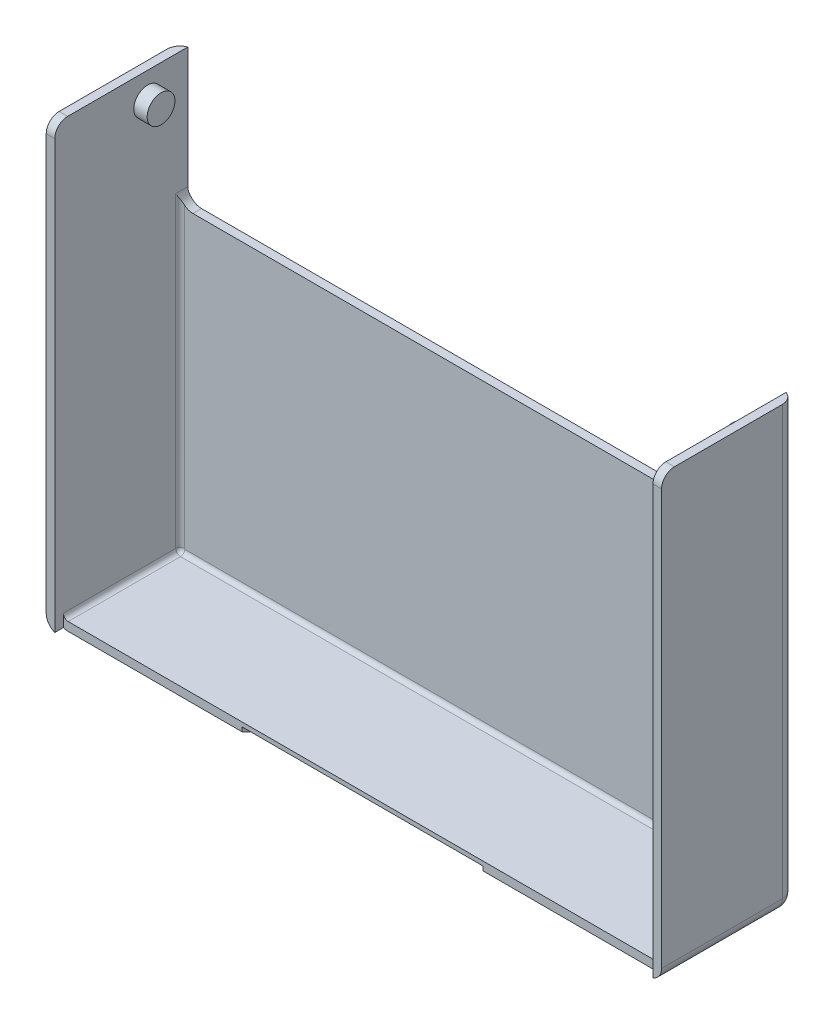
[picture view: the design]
ISO-10303-21;
HEADER;
FILE_DESCRIPTION(('STEP AP214'),'2;1');
FILE_NAME('part.step','',(''),(''),'','','');
FILE_SCHEMA(('AUTOMOTIVE_DESIGN { 1 0 10303 214 1 1 1 1 }'));
ENDSEC;
DATA;
#1=APPLICATION_CONTEXT('core data for automotive mechanical design processes');
#2=APPLICATION_PROTOCOL_DEFINITION('international standard','automotive_design',2000,#1);
#3=PRODUCT_CONTEXT('',#1,'mechanical');
#4=PRODUCT('Part','Part','',(#3));
#5=PRODUCT_RELATED_PRODUCT_CATEGORY('part','',(#4));
#6=PRODUCT_DEFINITION_FORMATION('','',#4);
#7=PRODUCT_DEFINITION_CONTEXT('part definition',#1,'design');
#8=PRODUCT_DEFINITION('design','',#6,#7);
#9=PRODUCT_DEFINITION_SHAPE('','',#8);
#10=(LENGTH_UNIT() NAMED_UNIT(*) SI_UNIT(.MILLI.,.METRE.));
#11=(NAMED_UNIT(*) PLANE_ANGLE_UNIT() SI_UNIT($,.RADIAN.));
#12=(NAMED_UNIT(*) SI_UNIT($,.STERADIAN.) SOLID_ANGLE_UNIT());
#13=UNCERTAINTY_MEASURE_WITH_UNIT(LENGTH_MEASURE(1.E-05),#10,'distance_accuracy_value','');
#14=(GEOMETRIC_REPRESENTATION_CONTEXT(3) GLOBAL_UNCERTAINTY_ASSIGNED_CONTEXT((#13)) GLOBAL_UNIT_ASSIGNED_CONTEXT((#10,
#11,#12)) REPRESENTATION_CONTEXT('',''));
#15=CARTESIAN_POINT('',(0.,0.,0.));
#16=DIRECTION('',(0.,0.,1.));
#17=DIRECTION('',(1.,0.,0.));
#18=AXIS2_PLACEMENT_3D('',#15,#16,#17);
#19=CARTESIAN_POINT('',(-36.5125,52.3875,7.9375));
#20=DIRECTION('',(0.,0.,-1.));
#21=DIRECTION('',(-1.,0.,0.));
#22=AXIS2_PLACEMENT_3D('',#19,#20,#21);
#23=PLANE('',#22);
#24=CARTESIAN_POINT('',(-34.925,1.5875,7.9375));
#25=DIRECTION('',(0.,0.,-1.));
#26=DIRECTION('',(-1.,0.,0.));
#27=AXIS2_PLACEMENT_3D('',#24,#25,#26);
#28=CIRCLE('',#27,1.5875);
#29=CARTESIAN_POINT('',(-36.5125,1.5875,7.9375));
#30=VERTEX_POINT('',#29);
#31=CARTESIAN_POINT('',(-35.4965,0.106438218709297,7.9375));
#32=VERTEX_POINT('',#31);
#33=EDGE_CURVE('E398',#30,#32,#28,.F.);
#34=ORIENTED_EDGE('',*,*,#33,.T.);
#35=DIRECTION('',(0.,-1.,0.));
#36=VECTOR('',#35,1.);
#37=CARTESIAN_POINT('',(-35.4965,52.3875,7.9375));
#38=LINE('',#37,#36);
#39=CARTESIAN_POINT('',(-35.4965,50.8635,7.9375));
#40=VERTEX_POINT('',#39);
#41=EDGE_CURVE('E365',#40,#32,#38,.T.);
#42=ORIENTED_EDGE('',*,*,#41,.F.);
#43=DIRECTION('',(-1.,0.,0.));
#44=VECTOR('',#43,1.);
#45=CARTESIAN_POINT('',(-36.5125,50.8635,7.9375));
#46=LINE('',#45,#44);
#47=CARTESIAN_POINT('',(-36.5125,50.8635,7.9375));
#48=VERTEX_POINT('',#47);
#49=EDGE_CURVE('E435',#40,#48,#46,.T.);
#50=ORIENTED_EDGE('',*,*,#49,.T.);
#51=DIRECTION('',(0.,-1.,0.));
#52=VECTOR('',#51,1.);
#53=CARTESIAN_POINT('',(-36.5125,0.,7.9375));
#54=LINE('',#53,#52);
#55=EDGE_CURVE('E381',#48,#30,#54,.T.);
#56=ORIENTED_EDGE('',*,*,#55,.T.);
#57=EDGE_LOOP('',(#34,#42,#50,#56));
#58=FACE_BOUND('',#57,.T.);
#59=ADVANCED_FACE('F33',(#58),#23,.F.);
#60=CARTESIAN_POINT('',(-35.4965,0.,7.9375));
#61=DIRECTION('',(1.,0.,0.));
#62=DIRECTION('',(0.,0.,-1.));
#63=AXIS2_PLACEMENT_3D('',#60,#61,#62);
#64=PLANE('',#63);
#65=CARTESIAN_POINT('',(-35.4965,50.8635,6.4135));
#66=DIRECTION('',(1.,0.,0.));
#67=DIRECTION('',(0.,0.,-1.));
#68=AXIS2_PLACEMENT_3D('',#65,#66,#67);
#69=CIRCLE('',#68,1.524);
#70=CARTESIAN_POINT('',(-35.4965,52.3875,6.4135));
#71=VERTEX_POINT('',#70);
#72=EDGE_CURVE('E456',#71,#40,#69,.T.);
#73=ORIENTED_EDGE('',*,*,#72,.T.);
#74=ORIENTED_EDGE('',*,*,#41,.T.);
#75=DIRECTION('',(0.,0.,-1.));
#76=VECTOR('',#75,1.);
#77=CARTESIAN_POINT('',(-35.4965,0.106438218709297,7.9375));
#78=LINE('',#77,#76);
#79=CARTESIAN_POINT('',(-35.4965,0.106438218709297,6.9215));
#80=VERTEX_POINT('',#79);
#81=EDGE_CURVE('E278',#32,#80,#78,.T.);
#82=ORIENTED_EDGE('',*,*,#81,.T.);
#83=DIRECTION('',(0.,-1.,0.));
#84=VECTOR('',#83,1.);
#85=CARTESIAN_POINT('',(-35.4965,52.3875,6.9215));
#86=LINE('',#85,#84);
#87=CARTESIAN_POINT('',(-35.4965,1.5875,6.9215));
#88=VERTEX_POINT('',#87);
#89=EDGE_CURVE('E56',#88,#80,#86,.T.);
#90=ORIENTED_EDGE('',*,*,#89,.F.);
#91=DIRECTION('',(0.,0.,-1.));
#92=VECTOR('',#91,1.);
#93=CARTESIAN_POINT('',(-35.4965,1.5875,7.9375));
#94=LINE('',#93,#92);
#95=CARTESIAN_POINT('',(-35.4965,1.5875,-6.4135));
#96=VERTEX_POINT('',#95);
#97=EDGE_CURVE('E325',#96,#88,#94,.F.);
#98=ORIENTED_EDGE('',*,*,#97,.F.);
#99=DIRECTION('',(0.,1.,0.));
#100=VECTOR('',#99,1.);
#101=CARTESIAN_POINT('',(-35.4965,0.,-6.4135));
#102=LINE('',#101,#100);
#103=CARTESIAN_POINT('',(-35.4965,38.0365,-6.4135));
#104=VERTEX_POINT('',#103);
#105=EDGE_CURVE('E322',#104,#96,#102,.F.);
#106=ORIENTED_EDGE('',*,*,#105,.F.);
#107=DIRECTION('',(0.,0.,1.));
#108=VECTOR('',#107,1.);
#109=CARTESIAN_POINT('',(-35.4965,38.0365,7.9375));
#110=LINE('',#109,#108);
#111=CARTESIAN_POINT('',(-35.4965,38.0365,-7.85034097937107));
#112=VERTEX_POINT('',#111);
#113=EDGE_CURVE('E454',#104,#112,#110,.F.);
#114=ORIENTED_EDGE('',*,*,#113,.T.);
#115=DIRECTION('',(0.,1.,0.));
#116=VECTOR('',#115,1.);
#117=CARTESIAN_POINT('',(-35.4965,0.,-7.85034097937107));
#118=LINE('',#117,#116);
#119=CARTESIAN_POINT('',(-35.4965,52.3875,-7.85034097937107));
#120=VERTEX_POINT('',#119);
#121=EDGE_CURVE('E316',#112,#120,#118,.T.);
#122=ORIENTED_EDGE('',*,*,#121,.T.);
#123=DIRECTION('',(0.,0.,1.));
#124=VECTOR('',#123,1.);
#125=CARTESIAN_POINT('',(-35.4965,52.3875,-7.9375));
#126=LINE('',#125,#124);
#127=EDGE_CURVE('E308',#120,#71,#126,.T.);
#128=ORIENTED_EDGE('',*,*,#127,.T.);
#129=EDGE_LOOP('',(#73,#74,#82,#90,#98,#106,#114,#122,#128));
#130=FACE_BOUND('',#129,.T.);
#131=CARTESIAN_POINT('',(-35.4965,49.2125,-3.0878409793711));
#132=DIRECTION('',(1.,0.,0.));
#133=DIRECTION('',(0.,0.,-1.));
#134=AXIS2_PLACEMENT_3D('',#131,#132,#133);
#135=CIRCLE('',#134,1.651);
#136=CARTESIAN_POINT('',(-35.4965,49.2125,-4.7388409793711));
#137=VERTEX_POINT('',#136);
#138=EDGE_CURVE('E298',#137,#137,#135,.T.);
#139=ORIENTED_EDGE('',*,*,#138,.F.);
#140=EDGE_LOOP('',(#139));
#141=FACE_BOUND('',#140,.T.);
#142=ADVANCED_FACE('F567',(#130,#141),#64,.T.);
#143=CARTESIAN_POINT('',(-36.5125,52.3875,7.9375));
#144=DIRECTION('',(0.,-1.,0.));
#145=DIRECTION('',(0.,0.,-1.));
#146=AXIS2_PLACEMENT_3D('',#143,#144,#145);
#147=PLANE('',#146);
#148=DIRECTION('',(0.,0.,1.));
#149=VECTOR('',#148,1.);
#150=CARTESIAN_POINT('',(35.4965,52.3875,-7.9375));
#151=LINE('',#150,#149);
#152=CARTESIAN_POINT('',(35.4965,52.3875,-7.85034097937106));
#153=VERTEX_POINT('',#152);
#154=CARTESIAN_POINT('',(35.4965,52.3875,6.4135));
#155=VERTEX_POINT('',#154);
#156=EDGE_CURVE('E307',#153,#155,#151,.T.);
#157=ORIENTED_EDGE('',*,*,#156,.T.);
#158=DIRECTION('',(-1.,0.,0.));
#159=VECTOR('',#158,1.);
#160=CARTESIAN_POINT('',(-36.5125,52.3875,6.4135));
#161=LINE('',#160,#159);
#162=CARTESIAN_POINT('',(36.5125,52.3875,6.4135));
#163=VERTEX_POINT('',#162);
#164=EDGE_CURVE('E446',#155,#163,#161,.F.);
#165=ORIENTED_EDGE('',*,*,#164,.T.);
#166=DIRECTION('',(0.,0.,-1.));
#167=VECTOR('',#166,1.);
#168=CARTESIAN_POINT('',(36.5125,52.3875,7.9375));
#169=LINE('',#168,#167);
#170=CARTESIAN_POINT('',(36.5125,52.3875,-6.4135));
#171=VERTEX_POINT('',#170);
#172=EDGE_CURVE('E388',#163,#171,#169,.T.);
#173=ORIENTED_EDGE('',*,*,#172,.T.);
#174=CARTESIAN_POINT('',(34.9885,52.3875,-6.4135));
#175=DIRECTION('',(0.,-1.,0.));
#176=DIRECTION('',(0.,0.,-1.));
#177=AXIS2_PLACEMENT_3D('',#174,#175,#176);
#178=CIRCLE('',#177,1.524);
#179=EDGE_CURVE('E419',#171,#153,#178,.F.);
#180=ORIENTED_EDGE('',*,*,#179,.T.);
#181=EDGE_LOOP('',(#157,#165,#173,#180));
#182=FACE_BOUND('',#181,.T.);
#183=ADVANCED_FACE('F574',(#182),#147,.F.);
#184=DIRECTION('',(0.,1.,0.));
#185=VECTOR('',#184,1.);
#186=CARTESIAN_POINT('',(35.4965,52.3875,7.9375));
#187=LINE('',#186,#185);
#188=CARTESIAN_POINT('',(35.4965,0.106438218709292,7.9375));
#189=VERTEX_POINT('',#188);
#190=CARTESIAN_POINT('',(35.4965,50.8635,7.9375));
#191=VERTEX_POINT('',#190);
#192=EDGE_CURVE('E332',#189,#191,#187,.T.);
#193=ORIENTED_EDGE('',*,*,#192,.F.);
#194=CARTESIAN_POINT('',(34.925,1.5875,7.9375));
#195=DIRECTION('',(0.,0.,-1.));
#196=DIRECTION('',(-1.,0.,0.));
#197=AXIS2_PLACEMENT_3D('',#194,#195,#196);
#198=CIRCLE('',#197,1.5875);
#199=CARTESIAN_POINT('',(36.5125,1.5875,7.9375));
#200=VERTEX_POINT('',#199);
#201=EDGE_CURVE('E401',#189,#200,#198,.F.);
#202=ORIENTED_EDGE('',*,*,#201,.T.);
#203=DIRECTION('',(0.,1.,0.));
#204=VECTOR('',#203,1.);
#205=CARTESIAN_POINT('',(36.5125,0.,7.9375));
#206=LINE('',#205,#204);
#207=CARTESIAN_POINT('',(36.5125,50.8635,7.9375));
#208=VERTEX_POINT('',#207);
#209=EDGE_CURVE('E383',#200,#208,#206,.T.);
#210=ORIENTED_EDGE('',*,*,#209,.T.);
#211=DIRECTION('',(-1.,0.,0.));
#212=VECTOR('',#211,1.);
#213=CARTESIAN_POINT('',(-36.5125,50.8635,7.9375));
#214=LINE('',#213,#212);
#215=EDGE_CURVE('E438',#208,#191,#214,.T.);
#216=ORIENTED_EDGE('',*,*,#215,.T.);
#217=EDGE_LOOP('',(#193,#202,#210,#216));
#218=FACE_BOUND('',#217,.T.);
#219=ADVANCED_FACE('F570',(#218),#23,.F.);
#220=CARTESIAN_POINT('',(-36.5125,0.,7.9375));
#221=DIRECTION('',(1.,0.,0.));
#222=DIRECTION('',(0.,0.,-1.));
#223=AXIS2_PLACEMENT_3D('',#220,#221,#222);
#224=PLANE('',#223);
#225=ORIENTED_EDGE('',*,*,#55,.F.);
#226=CARTESIAN_POINT('',(-36.5125,50.8635,6.4135));
#227=DIRECTION('',(1.,0.,0.));
#228=DIRECTION('',(0.,0.,-1.));
#229=AXIS2_PLACEMENT_3D('',#226,#227,#228);
#230=CIRCLE('',#229,1.524);
#231=CARTESIAN_POINT('',(-36.5125,52.3875,6.4135));
#232=VERTEX_POINT('',#231);
#233=EDGE_CURVE('E450',#48,#232,#230,.F.);
#234=ORIENTED_EDGE('',*,*,#233,.T.);
#235=DIRECTION('',(0.,0.,-1.));
#236=VECTOR('',#235,1.);
#237=CARTESIAN_POINT('',(-36.5125,52.3875,7.9375));
#238=LINE('',#237,#236);
#239=CARTESIAN_POINT('',(-36.5125,52.3875,-6.4135));
#240=VERTEX_POINT('',#239);
#241=EDGE_CURVE('E386',#232,#240,#238,.T.);
#242=ORIENTED_EDGE('',*,*,#241,.T.);
#243=DIRECTION('',(0.,-1.,0.));
#244=VECTOR('',#243,1.);
#245=CARTESIAN_POINT('',(-36.5125,1.5875,-6.4135));
#246=LINE('',#245,#244);
#247=CARTESIAN_POINT('',(-36.5125,1.5875,-6.4135));
#248=VERTEX_POINT('',#247);
#249=EDGE_CURVE('E406',#240,#248,#246,.T.);
#250=ORIENTED_EDGE('',*,*,#249,.T.);
#251=DIRECTION('',(0.,0.,-1.));
#252=VECTOR('',#251,1.);
#253=CARTESIAN_POINT('',(-36.5125,1.5875,7.9375));
#254=LINE('',#253,#252);
#255=EDGE_CURVE('E403',#248,#30,#254,.F.);
#256=ORIENTED_EDGE('',*,*,#255,.T.);
#257=EDGE_LOOP('',(#225,#234,#242,#250,#256));
#258=FACE_BOUND('',#257,.T.);
#259=ADVANCED_FACE('F35',(#258),#224,.F.);
#260=CARTESIAN_POINT('',(-36.5125,0.,7.9375));
#261=DIRECTION('',(0.,1.,0.));
#262=DIRECTION('',(0.,0.,1.));
#263=AXIS2_PLACEMENT_3D('',#260,#261,#262);
#264=PLANE('',#263);
#265=DIRECTION('',(1.,0.,0.));
#266=VECTOR('',#265,1.);
#267=CARTESIAN_POINT('',(35.4965,0.,6.9215));
#268=LINE('',#267,#266);
#269=CARTESIAN_POINT('',(14.2875,0.,6.9215));
#270=VERTEX_POINT('',#269);
#271=CARTESIAN_POINT('',(34.925,0.,6.9215));
#272=VERTEX_POINT('',#271);
#273=EDGE_CURVE('E270',#270,#272,#268,.T.);
#274=ORIENTED_EDGE('',*,*,#273,.F.);
#275=DIRECTION('',(0.707106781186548,0.,0.707106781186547));
#276=VECTOR('',#275,1.);
#277=CARTESIAN_POINT('',(14.2875,0.,6.9215));
#278=LINE('',#277,#276);
#279=CARTESIAN_POINT('',(11.5588692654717,0.,4.1928692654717));
#280=VERTEX_POINT('',#279);
#281=EDGE_CURVE('E894',#280,#270,#278,.T.);
#282=ORIENTED_EDGE('',*,*,#281,.F.);
#283=CARTESIAN_POINT('',(10.4812385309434,0.,5.2705));
#284=DIRECTION('',(0.,-1.,0.));
#285=DIRECTION('',(0.,0.,1.));
#286=AXIS2_PLACEMENT_3D('',#283,#284,#285);
#287=CIRCLE('',#286,1.524);
#288=CARTESIAN_POINT('',(10.4812385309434,0.,3.7465));
#289=VERTEX_POINT('',#288);
#290=EDGE_CURVE('E896',#289,#280,#287,.T.);
#291=ORIENTED_EDGE('',*,*,#290,.F.);
#292=DIRECTION('',(1.,0.,0.));
#293=VECTOR('',#292,1.);
#294=CARTESIAN_POINT('',(10.4812385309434,0.,3.7465));
#295=LINE('',#294,#293);
#296=CARTESIAN_POINT('',(-10.4812385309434,0.,3.7465));
#297=VERTEX_POINT('',#296);
#298=EDGE_CURVE('E900',#297,#289,#295,.T.);
#299=ORIENTED_EDGE('',*,*,#298,.F.);
#300=CARTESIAN_POINT('',(-10.4812385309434,0.,5.2705));
#301=DIRECTION('',(0.,-1.,0.));
#302=DIRECTION('',(0.,0.,1.));
#303=AXIS2_PLACEMENT_3D('',#300,#301,#302);
#304=CIRCLE('',#303,1.524);
#305=CARTESIAN_POINT('',(-11.5588692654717,0.,4.1928692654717));
#306=VERTEX_POINT('',#305);
#307=EDGE_CURVE('E265',#306,#297,#304,.T.);
#308=ORIENTED_EDGE('',*,*,#307,.F.);
#309=DIRECTION('',(0.707106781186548,0.,-0.707106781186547));
#310=VECTOR('',#309,1.);
#311=CARTESIAN_POINT('',(-11.5588692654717,0.,4.1928692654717));
#312=LINE('',#311,#310);
#313=CARTESIAN_POINT('',(-14.2875,0.,6.9215));
#314=VERTEX_POINT('',#313);
#315=EDGE_CURVE('E248',#314,#306,#312,.T.);
#316=ORIENTED_EDGE('',*,*,#315,.F.);
#317=CARTESIAN_POINT('',(-34.925,0.,6.9215));
#318=VERTEX_POINT('',#317);
#319=EDGE_CURVE('E261',#318,#314,#268,.T.);
#320=ORIENTED_EDGE('',*,*,#319,.F.);
#321=DIRECTION('',(0.,0.,-1.));
#322=VECTOR('',#321,1.);
#323=CARTESIAN_POINT('',(-34.925,0.,7.9375));
#324=LINE('',#323,#322);
#325=CARTESIAN_POINT('',(-34.925,0.,-6.4135));
#326=VERTEX_POINT('',#325);
#327=EDGE_CURVE('E393',#318,#326,#324,.T.);
#328=ORIENTED_EDGE('',*,*,#327,.T.);
#329=DIRECTION('',(1.,0.,0.));
#330=VECTOR('',#329,1.);
#331=CARTESIAN_POINT('',(34.925,0.,-6.4135));
#332=LINE('',#331,#330);
#333=CARTESIAN_POINT('',(34.925,0.,-6.4135));
#334=VERTEX_POINT('',#333);
#335=EDGE_CURVE('E428',#326,#334,#332,.T.);
#336=ORIENTED_EDGE('',*,*,#335,.T.);
#337=DIRECTION('',(0.,0.,-1.));
#338=VECTOR('',#337,1.);
#339=CARTESIAN_POINT('',(34.925,0.,7.9375));
#340=LINE('',#339,#338);
#341=EDGE_CURVE('E395',#334,#272,#340,.F.);
#342=ORIENTED_EDGE('',*,*,#341,.T.);
#343=EDGE_LOOP('',(#274,#282,#291,#299,#308,#316,#320,#328,#336,#342));
#344=FACE_BOUND('',#343,.T.);
#345=ADVANCED_FACE('F260',(#344),#264,.F.);
#346=CARTESIAN_POINT('',(36.5125,0.,7.9375));
#347=DIRECTION('',(-1.,0.,0.));
#348=DIRECTION('',(0.,0.,1.));
#349=AXIS2_PLACEMENT_3D('',#346,#347,#348);
#350=PLANE('',#349);
#351=ORIENTED_EDGE('',*,*,#172,.F.);
#352=CARTESIAN_POINT('',(36.5125,50.8635,6.4135));
#353=DIRECTION('',(-1.,0.,0.));
#354=DIRECTION('',(0.,0.,1.));
#355=AXIS2_PLACEMENT_3D('',#352,#353,#354);
#356=CIRCLE('',#355,1.524);
#357=EDGE_CURVE('E448',#163,#208,#356,.F.);
#358=ORIENTED_EDGE('',*,*,#357,.T.);
#359=ORIENTED_EDGE('',*,*,#209,.F.);
#360=DIRECTION('',(0.,0.,-1.));
#361=VECTOR('',#360,1.);
#362=CARTESIAN_POINT('',(36.5125,1.5875,7.9375));
#363=LINE('',#362,#361);
#364=CARTESIAN_POINT('',(36.5125,1.5875,-6.4135));
#365=VERTEX_POINT('',#364);
#366=EDGE_CURVE('E390',#200,#365,#363,.T.);
#367=ORIENTED_EDGE('',*,*,#366,.T.);
#368=DIRECTION('',(0.,1.,0.));
#369=VECTOR('',#368,1.);
#370=CARTESIAN_POINT('',(36.5125,52.3875,-6.4135));
#371=LINE('',#370,#369);
#372=EDGE_CURVE('E432',#365,#171,#371,.T.);
#373=ORIENTED_EDGE('',*,*,#372,.T.);
#374=EDGE_LOOP('',(#351,#358,#359,#367,#373));
#375=FACE_BOUND('',#374,.T.);
#376=ADVANCED_FACE('F604',(#375),#350,.F.);
#377=ORIENTED_EDGE('',*,*,#241,.F.);
#378=DIRECTION('',(-1.,0.,0.));
#379=VECTOR('',#378,1.);
#380=CARTESIAN_POINT('',(-36.5125,52.3875,6.4135));
#381=LINE('',#380,#379);
#382=EDGE_CURVE('E452',#232,#71,#381,.F.);
#383=ORIENTED_EDGE('',*,*,#382,.T.);
#384=ORIENTED_EDGE('',*,*,#127,.F.);
#385=CARTESIAN_POINT('',(-34.9885,52.3875,-6.4135));
#386=DIRECTION('',(0.,-1.,0.));
#387=DIRECTION('',(0.,0.,-1.));
#388=AXIS2_PLACEMENT_3D('',#385,#386,#387);
#389=CIRCLE('',#388,1.524);
#390=EDGE_CURVE('E422',#120,#240,#389,.F.);
#391=ORIENTED_EDGE('',*,*,#390,.T.);
#392=EDGE_LOOP('',(#377,#383,#384,#391));
#393=FACE_BOUND('',#392,.T.);
#394=ADVANCED_FACE('F586',(#393),#147,.F.);
#395=CARTESIAN_POINT('',(-36.5125,52.3875,-7.9375));
#396=DIRECTION('',(0.,0.,-1.));
#397=DIRECTION('',(-1.,0.,0.));
#398=AXIS2_PLACEMENT_3D('',#395,#396,#397);
#399=PLANE('',#398);
#400=DIRECTION('',(0.,-1.,0.));
#401=VECTOR('',#400,1.);
#402=CARTESIAN_POINT('',(-34.9885,52.3875,-7.9375));
#403=LINE('',#402,#401);
#404=CARTESIAN_POINT('',(-34.9885,1.5875,-7.9375));
#405=VERTEX_POINT('',#404);
#406=CARTESIAN_POINT('',(-34.9885,36.9005774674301,-7.9375));
#407=VERTEX_POINT('',#406);
#408=EDGE_CURVE('E417',#405,#407,#403,.F.);
#409=ORIENTED_EDGE('',*,*,#408,.T.);
#410=CARTESIAN_POINT('',(-33.9725,38.0365,-7.9375));
#411=DIRECTION('',(0.,0.,-1.));
#412=DIRECTION('',(-1.,0.,0.));
#413=AXIS2_PLACEMENT_3D('',#410,#411,#412);
#414=CIRCLE('',#413,1.524);
#415=CARTESIAN_POINT('',(-33.9725,36.5125,-7.9375));
#416=VERTEX_POINT('',#415);
#417=EDGE_CURVE('E41',#407,#416,#414,.F.);
#418=ORIENTED_EDGE('',*,*,#417,.T.);
#419=DIRECTION('',(1.,0.,0.));
#420=VECTOR('',#419,1.);
#421=CARTESIAN_POINT('',(-35.4965,36.5125,-7.9375));
#422=LINE('',#421,#420);
#423=CARTESIAN_POINT('',(33.9725,36.5125,-7.9375));
#424=VERTEX_POINT('',#423);
#425=EDGE_CURVE('E304',#416,#424,#422,.T.);
#426=ORIENTED_EDGE('',*,*,#425,.T.);
#427=CARTESIAN_POINT('',(33.9725,38.0365,-7.9375));
#428=DIRECTION('',(0.,0.,-1.));
#429=DIRECTION('',(-1.,0.,0.));
#430=AXIS2_PLACEMENT_3D('',#427,#428,#429);
#431=CIRCLE('',#430,1.524);
#432=CARTESIAN_POINT('',(34.9885,36.9005774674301,-7.9375));
#433=VERTEX_POINT('',#432);
#434=EDGE_CURVE('E620',#424,#433,#431,.F.);
#435=ORIENTED_EDGE('',*,*,#434,.T.);
#436=DIRECTION('',(0.,1.,0.));
#437=VECTOR('',#436,1.);
#438=CARTESIAN_POINT('',(34.9885,1.5875,-7.9375));
#439=LINE('',#438,#437);
#440=CARTESIAN_POINT('',(34.9885,1.5875,-7.9375));
#441=VERTEX_POINT('',#440);
#442=EDGE_CURVE('E409',#433,#441,#439,.F.);
#443=ORIENTED_EDGE('',*,*,#442,.T.);
#444=CARTESIAN_POINT('',(34.925,1.5875,-7.9375));
#445=DIRECTION('',(0.,0.,-1.));
#446=DIRECTION('',(-1.,0.,0.));
#447=AXIS2_PLACEMENT_3D('',#444,#445,#446);
#448=CIRCLE('',#447,0.0635);
#449=CARTESIAN_POINT('',(34.925,1.524,-7.9375));
#450=VERTEX_POINT('',#449);
#451=EDGE_CURVE('E411',#441,#450,#448,.T.);
#452=ORIENTED_EDGE('',*,*,#451,.T.);
#453=DIRECTION('',(1.,0.,0.));
#454=VECTOR('',#453,1.);
#455=CARTESIAN_POINT('',(-34.925,1.524,-7.9375));
#456=LINE('',#455,#454);
#457=CARTESIAN_POINT('',(-34.925,1.524,-7.9375));
#458=VERTEX_POINT('',#457);
#459=EDGE_CURVE('E413',#450,#458,#456,.F.);
#460=ORIENTED_EDGE('',*,*,#459,.T.);
#461=CARTESIAN_POINT('',(-34.925,1.5875,-7.9375));
#462=DIRECTION('',(0.,0.,-1.));
#463=DIRECTION('',(-1.,0.,0.));
#464=AXIS2_PLACEMENT_3D('',#461,#462,#463);
#465=CIRCLE('',#464,0.0635);
#466=EDGE_CURVE('E415',#458,#405,#465,.T.);
#467=ORIENTED_EDGE('',*,*,#466,.T.);
#468=EDGE_LOOP('',(#409,#418,#426,#435,#443,#452,#460,#467));
#469=FACE_BOUND('',#468,.T.);
#470=ADVANCED_FACE('F616',(#469),#399,.T.);
#471=CARTESIAN_POINT('',(34.925,1.5875,7.9375));
#472=DIRECTION('',(0.,0.,-1.));
#473=DIRECTION('',(-1.,0.,0.));
#474=AXIS2_PLACEMENT_3D('',#471,#472,#473);
#475=CYLINDRICAL_SURFACE('',#474,1.5875);
#476=DIRECTION('',(0.,0.,-1.));
#477=VECTOR('',#476,1.);
#478=CARTESIAN_POINT('',(35.4965,0.106438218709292,7.9375));
#479=LINE('',#478,#477);
#480=CARTESIAN_POINT('',(35.4965,0.106438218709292,6.9215));
#481=VERTEX_POINT('',#480);
#482=EDGE_CURVE('E292',#481,#189,#479,.F.);
#483=ORIENTED_EDGE('',*,*,#482,.F.);
#484=CARTESIAN_POINT('',(34.925,1.5875,6.9215));
#485=DIRECTION('',(0.,0.,-1.));
#486=DIRECTION('',(-1.,0.,0.));
#487=AXIS2_PLACEMENT_3D('',#484,#485,#486);
#488=CIRCLE('',#487,1.5875);
#489=EDGE_CURVE('E290',#272,#481,#488,.F.);
#490=ORIENTED_EDGE('',*,*,#489,.F.);
#491=ORIENTED_EDGE('',*,*,#341,.F.);
#492=CARTESIAN_POINT('',(34.925,1.5875,-6.4135));
#493=DIRECTION('',(0.,0.,-1.));
#494=DIRECTION('',(-1.,0.,0.));
#495=AXIS2_PLACEMENT_3D('',#492,#493,#494);
#496=CIRCLE('',#495,1.5875);
#497=EDGE_CURVE('E430',#334,#365,#496,.F.);
#498=ORIENTED_EDGE('',*,*,#497,.T.);
#499=ORIENTED_EDGE('',*,*,#366,.F.);
#500=ORIENTED_EDGE('',*,*,#201,.F.);
#501=EDGE_LOOP('',(#483,#490,#491,#498,#499,#500));
#502=FACE_BOUND('',#501,.T.);
#503=ADVANCED_FACE('F598',(#502),#475,.T.);
#504=CARTESIAN_POINT('',(-34.925,1.5875,7.9375));
#505=DIRECTION('',(0.,0.,-1.));
#506=DIRECTION('',(-1.,0.,0.));
#507=AXIS2_PLACEMENT_3D('',#504,#505,#506);
#508=CYLINDRICAL_SURFACE('',#507,1.5875);
#509=ORIENTED_EDGE('',*,*,#81,.F.);
#510=ORIENTED_EDGE('',*,*,#33,.F.);
#511=ORIENTED_EDGE('',*,*,#255,.F.);
#512=CARTESIAN_POINT('',(-34.925,1.5875,-6.4135));
#513=DIRECTION('',(0.,0.,-1.));
#514=DIRECTION('',(-1.,0.,0.));
#515=AXIS2_PLACEMENT_3D('',#512,#513,#514);
#516=CIRCLE('',#515,1.5875);
#517=EDGE_CURVE('E425',#248,#326,#516,.F.);
#518=ORIENTED_EDGE('',*,*,#517,.T.);
#519=ORIENTED_EDGE('',*,*,#327,.F.);
#520=CARTESIAN_POINT('',(-34.925,1.5875,6.9215));
#521=DIRECTION('',(0.,0.,-1.));
#522=DIRECTION('',(-1.,0.,0.));
#523=AXIS2_PLACEMENT_3D('',#520,#521,#522);
#524=CIRCLE('',#523,1.5875);
#525=EDGE_CURVE('E269',#80,#318,#524,.F.);
#526=ORIENTED_EDGE('',*,*,#525,.F.);
#527=EDGE_LOOP('',(#509,#510,#511,#518,#519,#526));
#528=FACE_BOUND('',#527,.T.);
#529=ADVANCED_FACE('F672',(#528),#508,.T.);
#530=CARTESIAN_POINT('',(34.9885,0.,-6.4135));
#531=DIRECTION('',(0.,-1.,0.));
#532=DIRECTION('',(0.,0.,-1.));
#533=AXIS2_PLACEMENT_3D('',#530,#531,#532);
#534=CYLINDRICAL_SURFACE('',#533,1.524);
#535=DIRECTION('',(0.,-1.,0.));
#536=VECTOR('',#535,1.);
#537=CARTESIAN_POINT('',(35.4964999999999,0.,-7.8503409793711));
#538=LINE('',#537,#536);
#539=CARTESIAN_POINT('',(35.4964999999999,38.0365,-7.8503409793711));
#540=VERTEX_POINT('',#539);
#541=EDGE_CURVE('E318',#153,#540,#538,.T.);
#542=ORIENTED_EDGE('',*,*,#541,.F.);
#543=ORIENTED_EDGE('',*,*,#179,.F.);
#544=ORIENTED_EDGE('',*,*,#372,.F.);
#545=CARTESIAN_POINT('',(34.9885,1.5875,-6.4135));
#546=DIRECTION('',(0.,-1.,0.));
#547=DIRECTION('',(0.,0.,-1.));
#548=AXIS2_PLACEMENT_3D('',#545,#546,#547);
#549=CIRCLE('',#548,1.524);
#550=EDGE_CURVE('E378',#441,#365,#549,.T.);
#551=ORIENTED_EDGE('',*,*,#550,.F.);
#552=ORIENTED_EDGE('',*,*,#442,.F.);
#553=CARTESIAN_POINT('',(34.9885,36.9005774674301,-7.9375));
#554=CARTESIAN_POINT('',(35.0199458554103,36.9287012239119,-7.93749931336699));
#555=CARTESIAN_POINT('',(35.050192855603,36.9581084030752,-7.93652707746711));
#556=CARTESIAN_POINT('',(35.1080890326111,37.0192563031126,-7.93307721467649));
#557=CARTESIAN_POINT('',(35.1357402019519,37.0509952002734,-7.93060075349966));
#558=CARTESIAN_POINT('',(35.2145310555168,37.1493790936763,-7.92157235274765));
#559=CARTESIAN_POINT('',(35.2615559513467,37.2192342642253,-7.91342007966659));
#560=CARTESIAN_POINT('',(35.3433670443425,37.365439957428,-7.89619902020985));
#561=CARTESIAN_POINT('',(35.3781731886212,37.4417796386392,-7.8871317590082));
#562=CARTESIAN_POINT('',(35.4348120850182,37.599249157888,-7.87098280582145));
#563=CARTESIAN_POINT('',(35.4566684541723,37.6803699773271,-7.86389751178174));
#564=CARTESIAN_POINT('',(35.4799523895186,37.8078743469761,-7.85610951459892));
#565=CARTESIAN_POINT('',(35.4861490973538,37.8533460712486,-7.8539694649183));
#566=CARTESIAN_POINT('',(35.4944243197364,37.9447029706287,-7.85107577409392));
#567=CARTESIAN_POINT('',(35.4965030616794,37.9905881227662,-7.85032205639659));
#568=CARTESIAN_POINT('',(35.4965,38.0365,-7.85034097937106));
#569=B_SPLINE_CURVE_WITH_KNOTS('',3,(#553,#554,#555,#556,#557,#558,#559,#560,#561,#562,#563,
#564,#565,#566,#567,#568),.UNSPECIFIED.,.F.,.F.,(4,2,2,2,2,2,2,4),(0.,0.126450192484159,
0.252802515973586,0.505316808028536,0.757416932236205,1.00905586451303,1.14669530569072,
1.28432714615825),.UNSPECIFIED.);
#570=EDGE_CURVE('E622',#433,#540,#569,.T.);
#571=ORIENTED_EDGE('',*,*,#570,.T.);
#572=EDGE_LOOP('',(#542,#543,#544,#551,#552,#571));
#573=FACE_BOUND('',#572,.T.);
#574=ADVANCED_FACE('F609',(#573),#534,.T.);
#575=CARTESIAN_POINT('',(34.925,1.5875,-6.4135));
#576=DIRECTION('',(0.,0.,-1.));
#577=DIRECTION('',(-1.,0.,0.));
#578=AXIS2_PLACEMENT_3D('',#575,#576,#577);
#579=DEGENERATE_TOROIDAL_SURFACE('',#578,0.0635,1.524,.T.);
#580=ORIENTED_EDGE('',*,*,#550,.T.);
#581=ORIENTED_EDGE('',*,*,#497,.F.);
#582=CARTESIAN_POINT('',(34.925,1.524,-6.4135));
#583=DIRECTION('',(-1.,0.,0.));
#584=DIRECTION('',(0.,0.,1.));
#585=AXIS2_PLACEMENT_3D('',#582,#583,#584);
#586=CIRCLE('',#585,1.524);
#587=EDGE_CURVE('E375',#450,#334,#586,.T.);
#588=ORIENTED_EDGE('',*,*,#587,.F.);
#589=ORIENTED_EDGE('',*,*,#451,.F.);
#590=EDGE_LOOP('',(#580,#581,#588,#589));
#591=FACE_BOUND('',#590,.T.);
#592=ADVANCED_FACE('F612',(#591),#579,.T.);
#593=CARTESIAN_POINT('',(-36.5125,1.524,-6.4135));
#594=DIRECTION('',(-1.,0.,0.));
#595=DIRECTION('',(0.,0.,1.));
#596=AXIS2_PLACEMENT_3D('',#593,#594,#595);
#597=CYLINDRICAL_SURFACE('',#596,1.524);
#598=ORIENTED_EDGE('',*,*,#587,.T.);
#599=ORIENTED_EDGE('',*,*,#335,.F.);
#600=CARTESIAN_POINT('',(-34.925,1.524,-6.4135));
#601=DIRECTION('',(-1.,0.,0.));
#602=DIRECTION('',(0.,0.,1.));
#603=AXIS2_PLACEMENT_3D('',#600,#601,#602);
#604=CIRCLE('',#603,1.524);
#605=EDGE_CURVE('E372',#458,#326,#604,.T.);
#606=ORIENTED_EDGE('',*,*,#605,.F.);
#607=ORIENTED_EDGE('',*,*,#459,.F.);
#608=EDGE_LOOP('',(#598,#599,#606,#607));
#609=FACE_BOUND('',#608,.T.);
#610=ADVANCED_FACE('F925',(#609),#597,.T.);
#611=CARTESIAN_POINT('',(-34.925,1.5875,-6.4135));
#612=DIRECTION('',(0.,0.,-1.));
#613=DIRECTION('',(-1.,0.,0.));
#614=AXIS2_PLACEMENT_3D('',#611,#612,#613);
#615=DEGENERATE_TOROIDAL_SURFACE('',#614,0.0635,1.524,.T.);
#616=ORIENTED_EDGE('',*,*,#605,.T.);
#617=ORIENTED_EDGE('',*,*,#517,.F.);
#618=CARTESIAN_POINT('',(-34.9885,1.5875,-6.4135));
#619=DIRECTION('',(0.,1.,0.));
#620=DIRECTION('',(0.,0.,1.));
#621=AXIS2_PLACEMENT_3D('',#618,#619,#620);
#622=CIRCLE('',#621,1.524);
#623=EDGE_CURVE('E335',#405,#248,#622,.T.);
#624=ORIENTED_EDGE('',*,*,#623,.F.);
#625=ORIENTED_EDGE('',*,*,#466,.F.);
#626=EDGE_LOOP('',(#616,#617,#624,#625));
#627=FACE_BOUND('',#626,.T.);
#628=ADVANCED_FACE('F729',(#627),#615,.T.);
#629=CARTESIAN_POINT('',(-34.9885,0.,-6.4135));
#630=DIRECTION('',(0.,1.,0.));
#631=DIRECTION('',(0.,0.,1.));
#632=AXIS2_PLACEMENT_3D('',#629,#630,#631);
#633=CYLINDRICAL_SURFACE('',#632,1.524);
#634=ORIENTED_EDGE('',*,*,#121,.F.);
#635=CARTESIAN_POINT('',(-35.4965,38.0365,-7.85034097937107));
#636=CARTESIAN_POINT('',(-35.4965056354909,37.9943062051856,-7.85032425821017));
#637=CARTESIAN_POINT('',(-35.4947479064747,37.952118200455,-7.85096013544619));
#638=CARTESIAN_POINT('',(-35.4877505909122,37.8680836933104,-7.85341310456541));
#639=CARTESIAN_POINT('',(-35.4825124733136,37.8262370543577,-7.85522969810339));
#640=CARTESIAN_POINT('',(-35.4686053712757,37.7432160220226,-7.85991822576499));
#641=CARTESIAN_POINT('',(-35.4599394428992,37.702041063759,-7.86278921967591));
#642=CARTESIAN_POINT('',(-35.4392594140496,37.6206169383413,-7.8693533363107));
#643=CARTESIAN_POINT('',(-35.4272451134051,37.5803678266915,-7.87304650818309));
#644=CARTESIAN_POINT('',(-35.3863339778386,37.4614675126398,-7.88493452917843));
#645=CARTESIAN_POINT('',(-35.3525458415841,37.384527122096,-7.89394720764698));
#646=CARTESIAN_POINT('',(-35.2728225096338,37.2372907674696,-7.91129430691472));
#647=CARTESIAN_POINT('',(-35.2269069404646,37.1669843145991,-7.91962979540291));
#648=CARTESIAN_POINT('',(-35.1474325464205,37.0648026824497,-7.92945287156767));
#649=CARTESIAN_POINT('',(-35.1177585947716,37.0299977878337,-7.93233056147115));
#650=CARTESIAN_POINT('',(-35.0553609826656,36.9631495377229,-7.93635336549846));
#651=CARTESIAN_POINT('',(-35.0226380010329,36.9311055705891,-7.93749886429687));
#652=CARTESIAN_POINT('',(-34.9885,36.9005774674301,-7.9375));
#653=B_SPLINE_CURVE_WITH_KNOTS('',3,(#635,#636,#637,#638,#639,#640,#641,#642,#643,#644,#645,
#646,#647,#648,#649,#650,#651,#652),.UNSPECIFIED.,.F.,.F.,(4,2,2,2,2,2,2,2,4),(0.,
0.126530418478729,0.253007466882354,0.379372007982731,0.505744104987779,0.75807812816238,
1.01000626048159,1.14729407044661,1.2845513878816),.UNSPECIFIED.);
#654=EDGE_CURVE('E514',#112,#407,#653,.T.);
#655=ORIENTED_EDGE('',*,*,#654,.T.);
#656=ORIENTED_EDGE('',*,*,#408,.F.);
#657=ORIENTED_EDGE('',*,*,#623,.T.);
#658=ORIENTED_EDGE('',*,*,#249,.F.);
#659=ORIENTED_EDGE('',*,*,#390,.F.);
#660=EDGE_LOOP('',(#634,#655,#656,#657,#658,#659));
#661=FACE_BOUND('',#660,.T.);
#662=ADVANCED_FACE('F503',(#661),#633,.T.);
#663=CARTESIAN_POINT('',(-36.5125,1.016,7.9375));
#664=DIRECTION('',(0.,1.,0.));
#665=DIRECTION('',(0.,0.,1.));
#666=AXIS2_PLACEMENT_3D('',#663,#664,#665);
#667=PLANE('',#666);
#668=DIRECTION('',(-1.,0.,0.));
#669=VECTOR('',#668,1.);
#670=CARTESIAN_POINT('',(-36.5125,1.016,6.9215));
#671=LINE('',#670,#669);
#672=CARTESIAN_POINT('',(34.925,1.016,6.9215));
#673=VERTEX_POINT('',#672);
#674=CARTESIAN_POINT('',(-34.925,1.016,6.9215));
#675=VERTEX_POINT('',#674);
#676=EDGE_CURVE('E284',#673,#675,#671,.T.);
#677=ORIENTED_EDGE('',*,*,#676,.F.);
#678=DIRECTION('',(0.,0.,1.));
#679=VECTOR('',#678,1.);
#680=CARTESIAN_POINT('',(34.925,1.016,7.9375));
#681=LINE('',#680,#679);
#682=CARTESIAN_POINT('',(34.925,1.016,-6.4135));
#683=VERTEX_POINT('',#682);
#684=EDGE_CURVE('E328',#683,#673,#681,.T.);
#685=ORIENTED_EDGE('',*,*,#684,.F.);
#686=DIRECTION('',(1.,0.,0.));
#687=VECTOR('',#686,1.);
#688=CARTESIAN_POINT('',(-36.5125,1.016,-6.4135));
#689=LINE('',#688,#687);
#690=CARTESIAN_POINT('',(-34.925,1.016,-6.4135));
#691=VERTEX_POINT('',#690);
#692=EDGE_CURVE('E341',#691,#683,#689,.T.);
#693=ORIENTED_EDGE('',*,*,#692,.F.);
#694=DIRECTION('',(0.,0.,1.));
#695=VECTOR('',#694,1.);
#696=CARTESIAN_POINT('',(-34.925,1.016,7.9375));
#697=LINE('',#696,#695);
#698=EDGE_CURVE('E331',#675,#691,#697,.F.);
#699=ORIENTED_EDGE('',*,*,#698,.F.);
#700=EDGE_LOOP('',(#677,#685,#693,#699));
#701=FACE_BOUND('',#700,.T.);
#702=ADVANCED_FACE('F650',(#701),#667,.T.);
#703=CARTESIAN_POINT('',(35.4965,0.,7.9375));
#704=DIRECTION('',(-1.,0.,0.));
#705=DIRECTION('',(0.,0.,1.));
#706=AXIS2_PLACEMENT_3D('',#703,#704,#705);
#707=PLANE('',#706);
#708=DIRECTION('',(0.,0.,1.));
#709=VECTOR('',#708,1.);
#710=CARTESIAN_POINT('',(35.4965,1.5875,7.9375));
#711=LINE('',#710,#709);
#712=CARTESIAN_POINT('',(35.4965,1.5875,6.9215));
#713=VERTEX_POINT('',#712);
#714=CARTESIAN_POINT('',(35.4965,1.5875,-6.4135));
#715=VERTEX_POINT('',#714);
#716=EDGE_CURVE('E329',#713,#715,#711,.F.);
#717=ORIENTED_EDGE('',*,*,#716,.F.);
#718=DIRECTION('',(0.,-1.,0.));
#719=VECTOR('',#718,1.);
#720=CARTESIAN_POINT('',(35.4965,52.3875,6.9215));
#721=LINE('',#720,#719);
#722=EDGE_CURVE('E272',#713,#481,#721,.T.);
#723=ORIENTED_EDGE('',*,*,#722,.T.);
#724=ORIENTED_EDGE('',*,*,#482,.T.);
#725=ORIENTED_EDGE('',*,*,#192,.T.);
#726=CARTESIAN_POINT('',(35.4965,50.8635,6.4135));
#727=DIRECTION('',(-1.,0.,0.));
#728=DIRECTION('',(0.,0.,1.));
#729=AXIS2_PLACEMENT_3D('',#726,#727,#728);
#730=CIRCLE('',#729,1.524);
#731=EDGE_CURVE('E444',#191,#155,#730,.T.);
#732=ORIENTED_EDGE('',*,*,#731,.T.);
#733=ORIENTED_EDGE('',*,*,#156,.F.);
#734=ORIENTED_EDGE('',*,*,#541,.T.);
#735=DIRECTION('',(0.,0.,1.));
#736=VECTOR('',#735,1.);
#737=CARTESIAN_POINT('',(35.4965,38.0365,7.9375));
#738=LINE('',#737,#736);
#739=CARTESIAN_POINT('',(35.4965,38.0365,-6.4135));
#740=VERTEX_POINT('',#739);
#741=EDGE_CURVE('E441',#540,#740,#738,.T.);
#742=ORIENTED_EDGE('',*,*,#741,.T.);
#743=DIRECTION('',(0.,1.,0.));
#744=VECTOR('',#743,1.);
#745=CARTESIAN_POINT('',(35.4965,0.,-6.4135));
#746=LINE('',#745,#744);
#747=EDGE_CURVE('E333',#715,#740,#746,.T.);
#748=ORIENTED_EDGE('',*,*,#747,.F.);
#749=EDGE_LOOP('',(#717,#723,#724,#725,#732,#733,#734,#742,#748));
#750=FACE_BOUND('',#749,.T.);
#751=CARTESIAN_POINT('',(35.4965,49.2125,-3.0878409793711));
#752=DIRECTION('',(-1.,0.,0.));
#753=DIRECTION('',(0.,0.,1.));
#754=AXIS2_PLACEMENT_3D('',#751,#752,#753);
#755=CIRCLE('',#754,1.651);
#756=CARTESIAN_POINT('',(35.4965,49.2125,-1.4368409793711));
#757=VERTEX_POINT('',#756);
#758=EDGE_CURVE('E11',#757,#757,#755,.T.);
#759=ORIENTED_EDGE('',*,*,#758,.F.);
#760=EDGE_LOOP('',(#759));
#761=FACE_BOUND('',#760,.T.);
#762=ADVANCED_FACE('F593',(#750,#761),#707,.T.);
#763=CARTESIAN_POINT('',(-36.5125,52.3875,-6.9215));
#764=DIRECTION('',(0.,0.,-1.));
#765=DIRECTION('',(-1.,0.,0.));
#766=AXIS2_PLACEMENT_3D('',#763,#764,#765);
#767=PLANE('',#766);
#768=DIRECTION('',(0.,1.,0.));
#769=VECTOR('',#768,1.);
#770=CARTESIAN_POINT('',(34.9885,52.3875,-6.9215));
#771=LINE('',#770,#769);
#772=CARTESIAN_POINT('',(34.9885,36.9005774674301,-6.9215));
#773=VERTEX_POINT('',#772);
#774=CARTESIAN_POINT('',(34.9885,1.5875,-6.9215));
#775=VERTEX_POINT('',#774);
#776=EDGE_CURVE('E324',#773,#775,#771,.F.);
#777=ORIENTED_EDGE('',*,*,#776,.F.);
#778=CARTESIAN_POINT('',(33.9725,38.0365,-6.9215));
#779=DIRECTION('',(0.,0.,-1.));
#780=DIRECTION('',(-1.,0.,0.));
#781=AXIS2_PLACEMENT_3D('',#778,#779,#780);
#782=CIRCLE('',#781,1.524);
#783=CARTESIAN_POINT('',(33.9725,36.5125,-6.9215));
#784=VERTEX_POINT('',#783);
#785=EDGE_CURVE('E471',#773,#784,#782,.T.);
#786=ORIENTED_EDGE('',*,*,#785,.T.);
#787=DIRECTION('',(-1.,0.,0.));
#788=VECTOR('',#787,1.);
#789=CARTESIAN_POINT('',(-36.5125,36.5125,-6.9215));
#790=LINE('',#789,#788);
#791=CARTESIAN_POINT('',(-33.9725,36.5125,-6.9215));
#792=VERTEX_POINT('',#791);
#793=EDGE_CURVE('E311',#784,#792,#790,.T.);
#794=ORIENTED_EDGE('',*,*,#793,.T.);
#795=CARTESIAN_POINT('',(-33.9725,38.0365,-6.9215));
#796=DIRECTION('',(0.,0.,-1.));
#797=DIRECTION('',(-1.,0.,0.));
#798=AXIS2_PLACEMENT_3D('',#795,#796,#797);
#799=CIRCLE('',#798,1.524);
#800=CARTESIAN_POINT('',(-34.9885,36.9005774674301,-6.9215));
#801=VERTEX_POINT('',#800);
#802=EDGE_CURVE('E515',#792,#801,#799,.T.);
#803=ORIENTED_EDGE('',*,*,#802,.T.);
#804=DIRECTION('',(0.,1.,0.));
#805=VECTOR('',#804,1.);
#806=CARTESIAN_POINT('',(-34.9885,52.3875,-6.9215));
#807=LINE('',#806,#805);
#808=CARTESIAN_POINT('',(-34.9885,1.5875,-6.9215));
#809=VERTEX_POINT('',#808);
#810=EDGE_CURVE('E347',#809,#801,#807,.T.);
#811=ORIENTED_EDGE('',*,*,#810,.F.);
#812=CARTESIAN_POINT('',(-34.925,1.5875,-6.9215));
#813=DIRECTION('',(0.,0.,-1.));
#814=DIRECTION('',(-1.,0.,0.));
#815=AXIS2_PLACEMENT_3D('',#812,#813,#814);
#816=CIRCLE('',#815,0.0635);
#817=CARTESIAN_POINT('',(-34.925,1.524,-6.9215));
#818=VERTEX_POINT('',#817);
#819=EDGE_CURVE('E357',#818,#809,#816,.T.);
#820=ORIENTED_EDGE('',*,*,#819,.F.);
#821=DIRECTION('',(-1.,0.,0.));
#822=VECTOR('',#821,1.);
#823=CARTESIAN_POINT('',(-36.5125,1.524,-6.9215));
#824=LINE('',#823,#822);
#825=CARTESIAN_POINT('',(34.925,1.524,-6.9215));
#826=VERTEX_POINT('',#825);
#827=EDGE_CURVE('E355',#826,#818,#824,.T.);
#828=ORIENTED_EDGE('',*,*,#827,.F.);
#829=CARTESIAN_POINT('',(34.925,1.5875,-6.9215));
#830=DIRECTION('',(0.,0.,-1.));
#831=DIRECTION('',(-1.,0.,0.));
#832=AXIS2_PLACEMENT_3D('',#829,#830,#831);
#833=CIRCLE('',#832,0.0635000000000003);
#834=EDGE_CURVE('E358',#775,#826,#833,.T.);
#835=ORIENTED_EDGE('',*,*,#834,.F.);
#836=EDGE_LOOP('',(#777,#786,#794,#803,#811,#820,#828,#835));
#837=FACE_BOUND('',#836,.T.);
#838=ADVANCED_FACE('F641',(#837),#767,.F.);
#839=CARTESIAN_POINT('',(34.925,1.5875,7.9375));
#840=DIRECTION('',(0.,0.,-1.));
#841=DIRECTION('',(-1.,0.,0.));
#842=AXIS2_PLACEMENT_3D('',#839,#840,#841);
#843=CYLINDRICAL_SURFACE('',#842,0.5715);
#844=ORIENTED_EDGE('',*,*,#684,.T.);
#845=CARTESIAN_POINT('',(34.925,1.5875,6.9215));
#846=DIRECTION('',(0.,0.,-1.));
#847=DIRECTION('',(-1.,0.,0.));
#848=AXIS2_PLACEMENT_3D('',#845,#846,#847);
#849=CIRCLE('',#848,0.5715);
#850=EDGE_CURVE('E286',#673,#713,#849,.F.);
#851=ORIENTED_EDGE('',*,*,#850,.T.);
#852=ORIENTED_EDGE('',*,*,#716,.T.);
#853=CARTESIAN_POINT('',(34.925,1.5875,-6.4135));
#854=DIRECTION('',(0.,0.,-1.));
#855=DIRECTION('',(-1.,0.,0.));
#856=AXIS2_PLACEMENT_3D('',#853,#854,#855);
#857=CIRCLE('',#856,0.5715);
#858=EDGE_CURVE('E336',#683,#715,#857,.F.);
#859=ORIENTED_EDGE('',*,*,#858,.F.);
#860=EDGE_LOOP('',(#844,#851,#852,#859));
#861=FACE_BOUND('',#860,.T.);
#862=ADVANCED_FACE('F632',(#861),#843,.F.);
#863=CARTESIAN_POINT('',(-34.925,1.5875,7.9375));
#864=DIRECTION('',(0.,0.,-1.));
#865=DIRECTION('',(-1.,0.,0.));
#866=AXIS2_PLACEMENT_3D('',#863,#864,#865);
#867=CYLINDRICAL_SURFACE('',#866,0.5715);
#868=ORIENTED_EDGE('',*,*,#97,.T.);
#869=CARTESIAN_POINT('',(-34.925,1.5875,6.9215));
#870=DIRECTION('',(0.,0.,-1.));
#871=DIRECTION('',(-1.,0.,0.));
#872=AXIS2_PLACEMENT_3D('',#869,#870,#871);
#873=CIRCLE('',#872,0.5715);
#874=EDGE_CURVE('E281',#88,#675,#873,.F.);
#875=ORIENTED_EDGE('',*,*,#874,.T.);
#876=ORIENTED_EDGE('',*,*,#698,.T.);
#877=CARTESIAN_POINT('',(-34.925,1.5875,-6.4135));
#878=DIRECTION('',(0.,0.,-1.));
#879=DIRECTION('',(-1.,0.,0.));
#880=AXIS2_PLACEMENT_3D('',#877,#878,#879);
#881=CIRCLE('',#880,0.5715);
#882=EDGE_CURVE('E344',#96,#691,#881,.F.);
#883=ORIENTED_EDGE('',*,*,#882,.F.);
#884=EDGE_LOOP('',(#868,#875,#876,#883));
#885=FACE_BOUND('',#884,.T.);
#886=ADVANCED_FACE('F483',(#885),#867,.F.);
#887=CARTESIAN_POINT('',(34.9885,0.,-6.4135));
#888=DIRECTION('',(0.,-1.,0.));
#889=DIRECTION('',(0.,0.,-1.));
#890=AXIS2_PLACEMENT_3D('',#887,#888,#889);
#891=CYLINDRICAL_SURFACE('',#890,0.508);
#892=ORIENTED_EDGE('',*,*,#747,.T.);
#893=CARTESIAN_POINT('',(34.9885,36.9005774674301,-6.9215));
#894=CARTESIAN_POINT('',(35.0207094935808,36.9293598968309,-6.92145922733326));
#895=CARTESIAN_POINT('',(35.0515397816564,36.9594245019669,-6.9184472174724));
#896=CARTESIAN_POINT('',(35.109970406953,37.0213549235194,-6.90765834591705));
#897=CARTESIAN_POINT('',(35.1375931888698,37.0532055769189,-6.89991731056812));
#898=CARTESIAN_POINT('',(35.2067207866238,37.1398066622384,-6.87453720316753));
#899=CARTESIAN_POINT('',(35.2454217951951,37.1958531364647,-6.85373654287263));
#900=CARTESIAN_POINT('',(35.3142448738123,37.310678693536,-6.80558287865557));
#901=CARTESIAN_POINT('',(35.3443116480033,37.3694727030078,-6.77818962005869));
#902=CARTESIAN_POINT('',(35.4070588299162,37.5138435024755,-6.70675022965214));
#903=CARTESIAN_POINT('',(35.4354537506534,37.600218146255,-6.66056459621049));
#904=CARTESIAN_POINT('',(35.4764007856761,37.7741559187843,-6.56430853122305));
#905=CARTESIAN_POINT('',(35.4889887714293,37.8617158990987,-6.51424717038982));
#906=CARTESIAN_POINT('',(35.4955398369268,37.9761382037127,-6.44834635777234));
#907=CARTESIAN_POINT('',(35.4963660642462,38.0029373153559,-6.43287715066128));
#908=CARTESIAN_POINT('',(35.4964950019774,38.0319922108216,-6.41610257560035));
#909=CARTESIAN_POINT('',(35.4965000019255,38.0342461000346,-6.41480129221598));
#910=CARTESIAN_POINT('',(35.4965,38.0365,-6.4135));
#911=B_SPLINE_CURVE_WITH_KNOTS('',3,(#893,#894,#895,#896,#897,#898,#899,#900,#901,#902,#903,
#904,#905,#906,#907,#908,#909,#910),.UNSPECIFIED.,.F.,.F.,(4,2,2,2,2,2,2,2,4),(0.,
0.129190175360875,0.257413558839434,0.469885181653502,0.683688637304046,0.988036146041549,
1.29169172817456,1.38453375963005,1.39234146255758),.UNSPECIFIED.);
#912=EDGE_CURVE('E463',#740,#773,#911,.F.);
#913=ORIENTED_EDGE('',*,*,#912,.T.);
#914=ORIENTED_EDGE('',*,*,#776,.T.);
#915=CARTESIAN_POINT('',(34.9885,1.5875,-6.4135));
#916=DIRECTION('',(0.,1.,0.));
#917=DIRECTION('',(-1.,0.,0.));
#918=AXIS2_PLACEMENT_3D('',#915,#916,#917);
#919=CIRCLE('',#918,0.508);
#920=EDGE_CURVE('E351',#775,#715,#919,.F.);
#921=ORIENTED_EDGE('',*,*,#920,.T.);
#922=EDGE_LOOP('',(#892,#913,#914,#921));
#923=FACE_BOUND('',#922,.T.);
#924=ADVANCED_FACE('F477',(#923),#891,.F.);
#925=CARTESIAN_POINT('',(34.925,1.5875,-6.4135));
#926=DIRECTION('',(0.,0.,-1.));
#927=DIRECTION('',(-1.,0.,0.));
#928=AXIS2_PLACEMENT_3D('',#925,#926,#927);
#929=DEGENERATE_TOROIDAL_SURFACE('',#928,0.0635,0.508,.T.);
#930=ORIENTED_EDGE('',*,*,#920,.F.);
#931=ORIENTED_EDGE('',*,*,#834,.T.);
#932=CARTESIAN_POINT('',(34.925,1.524,-6.4135));
#933=DIRECTION('',(-1.,0.,0.));
#934=DIRECTION('',(0.,0.,1.));
#935=AXIS2_PLACEMENT_3D('',#932,#933,#934);
#936=CIRCLE('',#935,0.508);
#937=EDGE_CURVE('E348',#826,#683,#936,.T.);
#938=ORIENTED_EDGE('',*,*,#937,.T.);
#939=ORIENTED_EDGE('',*,*,#858,.T.);
#940=EDGE_LOOP('',(#930,#931,#938,#939));
#941=FACE_BOUND('',#940,.T.);
#942=ADVANCED_FACE('F482',(#941),#929,.F.);
#943=CARTESIAN_POINT('',(-36.5125,1.524,-6.4135));
#944=DIRECTION('',(-1.,0.,0.));
#945=DIRECTION('',(0.,0.,1.));
#946=AXIS2_PLACEMENT_3D('',#943,#944,#945);
#947=CYLINDRICAL_SURFACE('',#946,0.508);
#948=ORIENTED_EDGE('',*,*,#937,.F.);
#949=ORIENTED_EDGE('',*,*,#827,.T.);
#950=CARTESIAN_POINT('',(-34.925,1.524,-6.4135));
#951=DIRECTION('',(1.,0.,0.));
#952=DIRECTION('',(0.,1.,0.));
#953=AXIS2_PLACEMENT_3D('',#950,#951,#952);
#954=CIRCLE('',#953,0.508);
#955=EDGE_CURVE('E352',#818,#691,#954,.F.);
#956=ORIENTED_EDGE('',*,*,#955,.T.);
#957=ORIENTED_EDGE('',*,*,#692,.T.);
#958=EDGE_LOOP('',(#948,#949,#956,#957));
#959=FACE_BOUND('',#958,.T.);
#960=ADVANCED_FACE('F488',(#959),#947,.F.);
#961=CARTESIAN_POINT('',(-34.925,1.5875,-6.4135));
#962=DIRECTION('',(0.,0.,-1.));
#963=DIRECTION('',(-1.,0.,0.));
#964=AXIS2_PLACEMENT_3D('',#961,#962,#963);
#965=DEGENERATE_TOROIDAL_SURFACE('',#964,0.0635,0.508,.T.);
#966=ORIENTED_EDGE('',*,*,#955,.F.);
#967=ORIENTED_EDGE('',*,*,#819,.T.);
#968=CARTESIAN_POINT('',(-34.9885,1.5875,-6.4135));
#969=DIRECTION('',(0.,1.,0.));
#970=DIRECTION('',(0.,0.,1.));
#971=AXIS2_PLACEMENT_3D('',#968,#969,#970);
#972=CIRCLE('',#971,0.508);
#973=EDGE_CURVE('E321',#809,#96,#972,.T.);
#974=ORIENTED_EDGE('',*,*,#973,.T.);
#975=ORIENTED_EDGE('',*,*,#882,.T.);
#976=EDGE_LOOP('',(#966,#967,#974,#975));
#977=FACE_BOUND('',#976,.T.);
#978=ADVANCED_FACE('F492',(#977),#965,.F.);
#979=CARTESIAN_POINT('',(-34.9885,0.,-6.4135));
#980=DIRECTION('',(0.,1.,0.));
#981=DIRECTION('',(0.,0.,1.));
#982=AXIS2_PLACEMENT_3D('',#979,#980,#981);
#983=CYLINDRICAL_SURFACE('',#982,0.508);
#984=ORIENTED_EDGE('',*,*,#810,.T.);
#985=CARTESIAN_POINT('',(-34.9885,36.9005774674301,-6.9215));
#986=CARTESIAN_POINT('',(-35.0207094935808,36.9293598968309,-6.92145922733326));
#987=CARTESIAN_POINT('',(-35.0515397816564,36.9594245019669,-6.9184472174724));
#988=CARTESIAN_POINT('',(-35.109970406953,37.0213549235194,-6.90765834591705));
#989=CARTESIAN_POINT('',(-35.1375931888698,37.0532055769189,-6.89991731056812));
#990=CARTESIAN_POINT('',(-35.2067207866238,37.1398066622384,-6.87453720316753));
#991=CARTESIAN_POINT('',(-35.2454217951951,37.1958531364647,-6.85373654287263));
#992=CARTESIAN_POINT('',(-35.3142448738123,37.310678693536,-6.80558287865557));
#993=CARTESIAN_POINT('',(-35.3443116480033,37.3694727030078,-6.77818962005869));
#994=CARTESIAN_POINT('',(-35.4070588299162,37.5138435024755,-6.70675022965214));
#995=CARTESIAN_POINT('',(-35.4354537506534,37.600218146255,-6.66056459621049));
#996=CARTESIAN_POINT('',(-35.4764007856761,37.7741559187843,-6.56430853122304));
#997=CARTESIAN_POINT('',(-35.4889887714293,37.8617158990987,-6.51424717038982));
#998=CARTESIAN_POINT('',(-35.4955398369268,37.9761382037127,-6.44834635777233));
#999=CARTESIAN_POINT('',(-35.4963660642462,38.0029373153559,-6.43287715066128));
#1000=CARTESIAN_POINT('',(-35.4964950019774,38.0319922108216,-6.41610257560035));
#1001=CARTESIAN_POINT('',(-35.4965000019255,38.0342461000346,-6.41480129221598));
#1002=CARTESIAN_POINT('',(-35.4965,38.0365,-6.4135));
#1003=B_SPLINE_CURVE_WITH_KNOTS('',3,(#985,#986,#987,#988,#989,#990,#991,#992,#993,#994,#995,
#996,#997,#998,#999,#1000,#1001,#1002),.UNSPECIFIED.,.F.,.F.,(4,2,2,2,2,2,2,2,4),(0.,
0.129190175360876,0.257413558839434,0.469885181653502,0.683688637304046,0.988036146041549,
1.29169172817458,1.38453375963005,1.39234146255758),.UNSPECIFIED.);
#1004=EDGE_CURVE('E507',#801,#104,#1003,.T.);
#1005=ORIENTED_EDGE('',*,*,#1004,.T.);
#1006=ORIENTED_EDGE('',*,*,#105,.T.);
#1007=ORIENTED_EDGE('',*,*,#973,.F.);
#1008=EDGE_LOOP('',(#984,#1005,#1006,#1007));
#1009=FACE_BOUND('',#1008,.T.);
#1010=ADVANCED_FACE('F496',(#1009),#983,.F.);
#1011=CARTESIAN_POINT('',(-35.4965,36.5125,-7.9375));
#1012=DIRECTION('',(0.,-1.,0.));
#1013=DIRECTION('',(0.,0.,-1.));
#1014=AXIS2_PLACEMENT_3D('',#1011,#1012,#1013);
#1015=PLANE('',#1014);
#1016=ORIENTED_EDGE('',*,*,#793,.F.);
#1017=DIRECTION('',(0.,0.,1.));
#1018=VECTOR('',#1017,1.);
#1019=CARTESIAN_POINT('',(33.9725,36.5125,-7.9375));
#1020=LINE('',#1019,#1018);
#1021=EDGE_CURVE('E461',#784,#424,#1020,.F.);
#1022=ORIENTED_EDGE('',*,*,#1021,.T.);
#1023=ORIENTED_EDGE('',*,*,#425,.F.);
#1024=DIRECTION('',(0.,0.,1.));
#1025=VECTOR('',#1024,1.);
#1026=CARTESIAN_POINT('',(-33.9725,36.5125,-7.9375));
#1027=LINE('',#1026,#1025);
#1028=EDGE_CURVE('E458',#416,#792,#1027,.T.);
#1029=ORIENTED_EDGE('',*,*,#1028,.T.);
#1030=EDGE_LOOP('',(#1016,#1022,#1023,#1029));
#1031=FACE_BOUND('',#1030,.T.);
#1032=ADVANCED_FACE('F501',(#1031),#1015,.F.);
#1033=CARTESIAN_POINT('',(-36.5125,50.8635,6.4135));
#1034=DIRECTION('',(-1.,0.,0.));
#1035=DIRECTION('',(0.,0.,1.));
#1036=AXIS2_PLACEMENT_3D('',#1033,#1034,#1035);
#1037=CYLINDRICAL_SURFACE('',#1036,1.524);
#1038=ORIENTED_EDGE('',*,*,#357,.F.);
#1039=ORIENTED_EDGE('',*,*,#164,.F.);
#1040=ORIENTED_EDGE('',*,*,#731,.F.);
#1041=ORIENTED_EDGE('',*,*,#215,.F.);
#1042=EDGE_LOOP('',(#1038,#1039,#1040,#1041));
#1043=FACE_BOUND('',#1042,.T.);
#1044=ADVANCED_FACE('F770',(#1043),#1037,.T.);
#1045=CARTESIAN_POINT('',(-36.5125,50.8635,6.4135));
#1046=DIRECTION('',(-1.,0.,0.));
#1047=DIRECTION('',(0.,0.,1.));
#1048=AXIS2_PLACEMENT_3D('',#1045,#1046,#1047);
#1049=CYLINDRICAL_SURFACE('',#1048,1.524);
#1050=ORIENTED_EDGE('',*,*,#72,.F.);
#1051=ORIENTED_EDGE('',*,*,#382,.F.);
#1052=ORIENTED_EDGE('',*,*,#233,.F.);
#1053=ORIENTED_EDGE('',*,*,#49,.F.);
#1054=EDGE_LOOP('',(#1050,#1051,#1052,#1053));
#1055=FACE_BOUND('',#1054,.T.);
#1056=ADVANCED_FACE('F782',(#1055),#1049,.T.);
#1057=CARTESIAN_POINT('',(33.9725,38.0365,7.9375));
#1058=DIRECTION('',(0.,0.,1.));
#1059=DIRECTION('',(1.,0.,0.));
#1060=AXIS2_PLACEMENT_3D('',#1057,#1058,#1059);
#1061=CYLINDRICAL_SURFACE('',#1060,1.524);
#1062=ORIENTED_EDGE('',*,*,#434,.F.);
#1063=ORIENTED_EDGE('',*,*,#1021,.F.);
#1064=ORIENTED_EDGE('',*,*,#785,.F.);
#1065=ORIENTED_EDGE('',*,*,#912,.F.);
#1066=ORIENTED_EDGE('',*,*,#741,.F.);
#1067=ORIENTED_EDGE('',*,*,#570,.F.);
#1068=EDGE_LOOP('',(#1062,#1063,#1064,#1065,#1066,#1067));
#1069=FACE_BOUND('',#1068,.T.);
#1070=ADVANCED_FACE('F473',(#1069),#1061,.F.);
#1071=CARTESIAN_POINT('',(-33.9725,38.0365,-7.9375));
#1072=DIRECTION('',(0.,0.,1.));
#1073=DIRECTION('',(1.,0.,0.));
#1074=AXIS2_PLACEMENT_3D('',#1071,#1072,#1073);
#1075=CYLINDRICAL_SURFACE('',#1074,1.524);
#1076=ORIENTED_EDGE('',*,*,#654,.F.);
#1077=ORIENTED_EDGE('',*,*,#113,.F.);
#1078=ORIENTED_EDGE('',*,*,#1004,.F.);
#1079=ORIENTED_EDGE('',*,*,#802,.F.);
#1080=ORIENTED_EDGE('',*,*,#1028,.F.);
#1081=ORIENTED_EDGE('',*,*,#417,.F.);
#1082=EDGE_LOOP('',(#1076,#1077,#1078,#1079,#1080,#1081));
#1083=FACE_BOUND('',#1082,.T.);
#1084=ADVANCED_FACE('F520',(#1083),#1075,.F.);
#1085=CARTESIAN_POINT('',(-33.909,49.2125,-3.0878409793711));
#1086=DIRECTION('',(-1.,0.,0.));
#1087=DIRECTION('',(0.,0.,1.));
#1088=AXIS2_PLACEMENT_3D('',#1085,#1086,#1087);
#1089=CYLINDRICAL_SURFACE('',#1088,1.651);
#1090=CARTESIAN_POINT('',(-33.909,49.2125,-3.0878409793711));
#1091=DIRECTION('',(1.,0.,0.));
#1092=DIRECTION('',(0.,0.,-1.));
#1093=AXIS2_PLACEMENT_3D('',#1090,#1091,#1092);
#1094=CIRCLE('',#1093,1.651);
#1095=CARTESIAN_POINT('',(-33.909,49.2125,-4.7388409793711));
#1096=VERTEX_POINT('',#1095);
#1097=EDGE_CURVE('E301',#1096,#1096,#1094,.T.);
#1098=ORIENTED_EDGE('',*,*,#1097,.F.);
#1099=EDGE_LOOP('',(#1098));
#1100=FACE_BOUND('',#1099,.T.);
#1101=ORIENTED_EDGE('',*,*,#138,.T.);
#1102=EDGE_LOOP('',(#1101));
#1103=FACE_BOUND('',#1102,.T.);
#1104=ADVANCED_FACE('F524',(#1100,#1103),#1089,.T.);
#1105=CARTESIAN_POINT('',(-33.909,49.2125,-3.0878409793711));
#1106=DIRECTION('',(1.,0.,0.));
#1107=DIRECTION('',(0.,0.,-1.));
#1108=AXIS2_PLACEMENT_3D('',#1105,#1106,#1107);
#1109=PLANE('',#1108);
#1110=ORIENTED_EDGE('',*,*,#1097,.T.);
#1111=EDGE_LOOP('',(#1110));
#1112=FACE_BOUND('',#1111,.T.);
#1113=ADVANCED_FACE('F529',(#1112),#1109,.T.);
#1114=CARTESIAN_POINT('',(33.909,49.2125,-3.0878409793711));
#1115=DIRECTION('',(1.,0.,0.));
#1116=DIRECTION('',(0.,0.,-1.));
#1117=AXIS2_PLACEMENT_3D('',#1114,#1115,#1116);
#1118=CYLINDRICAL_SURFACE('',#1117,1.651);
#1119=CARTESIAN_POINT('',(33.909,49.2125,-3.0878409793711));
#1120=DIRECTION('',(1.,0.,0.));
#1121=DIRECTION('',(0.,0.,-1.));
#1122=AXIS2_PLACEMENT_3D('',#1119,#1120,#1121);
#1123=CIRCLE('',#1122,1.651);
#1124=CARTESIAN_POINT('',(33.909,49.2125,-4.7388409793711));
#1125=VERTEX_POINT('',#1124);
#1126=EDGE_CURVE('E295',#1125,#1125,#1123,.T.);
#1127=ORIENTED_EDGE('',*,*,#1126,.T.);
#1128=EDGE_LOOP('',(#1127));
#1129=FACE_BOUND('',#1128,.T.);
#1130=ORIENTED_EDGE('',*,*,#758,.T.);
#1131=EDGE_LOOP('',(#1130));
#1132=FACE_BOUND('',#1131,.T.);
#1133=ADVANCED_FACE('F533',(#1129,#1132),#1118,.T.);
#1134=CARTESIAN_POINT('',(33.909,49.2125,-3.0878409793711));
#1135=DIRECTION('',(-1.,0.,0.));
#1136=DIRECTION('',(0.,0.,-1.));
#1137=AXIS2_PLACEMENT_3D('',#1134,#1135,#1136);
#1138=PLANE('',#1137);
#1139=ORIENTED_EDGE('',*,*,#1126,.F.);
#1140=EDGE_LOOP('',(#1139));
#1141=FACE_BOUND('',#1140,.T.);
#1142=ADVANCED_FACE('F537',(#1141),#1138,.T.);
#1143=CARTESIAN_POINT('',(35.4965,52.3875,6.9215));
#1144=DIRECTION('',(0.,0.,-1.));
#1145=DIRECTION('',(-1.,0.,0.));
#1146=AXIS2_PLACEMENT_3D('',#1143,#1144,#1145);
#1147=PLANE('',#1146);
#1148=DIRECTION('',(-1.,0.,0.));
#1149=VECTOR('',#1148,1.);
#1150=CARTESIAN_POINT('',(14.2875,0.508,6.9215));
#1151=LINE('',#1150,#1149);
#1152=CARTESIAN_POINT('',(14.2875,0.508000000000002,6.9215));
#1153=VERTEX_POINT('',#1152);
#1154=CARTESIAN_POINT('',(-14.2875,0.508,6.9215));
#1155=VERTEX_POINT('',#1154);
#1156=EDGE_CURVE('E897',#1153,#1155,#1151,.T.);
#1157=ORIENTED_EDGE('',*,*,#1156,.F.);
#1158=DIRECTION('',(0.,-1.,0.));
#1159=VECTOR('',#1158,1.);
#1160=CARTESIAN_POINT('',(14.2875,0.508,6.9215));
#1161=LINE('',#1160,#1159);
#1162=EDGE_CURVE('E274',#1153,#270,#1161,.T.);
#1163=ORIENTED_EDGE('',*,*,#1162,.T.);
#1164=ORIENTED_EDGE('',*,*,#273,.T.);
#1165=ORIENTED_EDGE('',*,*,#489,.T.);
#1166=ORIENTED_EDGE('',*,*,#722,.F.);
#1167=ORIENTED_EDGE('',*,*,#850,.F.);
#1168=ORIENTED_EDGE('',*,*,#676,.T.);
#1169=ORIENTED_EDGE('',*,*,#874,.F.);
#1170=ORIENTED_EDGE('',*,*,#89,.T.);
#1171=ORIENTED_EDGE('',*,*,#525,.T.);
#1172=ORIENTED_EDGE('',*,*,#319,.T.);
#1173=DIRECTION('',(0.,-1.,0.));
#1174=VECTOR('',#1173,1.);
#1175=CARTESIAN_POINT('',(-14.2875,0.508,6.9215));
#1176=LINE('',#1175,#1174);
#1177=EDGE_CURVE('E245',#1155,#314,#1176,.T.);
#1178=ORIENTED_EDGE('',*,*,#1177,.F.);
#1179=EDGE_LOOP('',(#1157,#1163,#1164,#1165,#1166,#1167,#1168,#1169,#1170,#1171,#1172,#1178));
#1180=FACE_BOUND('',#1179,.T.);
#1181=ADVANCED_FACE('F267',(#1180),#1147,.F.);
#1182=CARTESIAN_POINT('',(14.2875,0.508,6.9215));
#1183=DIRECTION('',(0.707106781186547,0.,-0.707106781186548));
#1184=DIRECTION('',(-0.707106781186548,0.,-0.707106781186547));
#1185=AXIS2_PLACEMENT_3D('',#1182,#1183,#1184);
#1186=PLANE('',#1185);
#1187=ORIENTED_EDGE('',*,*,#281,.T.);
#1188=ORIENTED_EDGE('',*,*,#1162,.F.);
#1189=DIRECTION('',(0.707106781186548,0.,0.707106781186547));
#1190=VECTOR('',#1189,1.);
#1191=CARTESIAN_POINT('',(14.2875,0.508,6.9215));
#1192=LINE('',#1191,#1190);
#1193=CARTESIAN_POINT('',(11.5588692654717,0.508,4.1928692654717));
#1194=VERTEX_POINT('',#1193);
#1195=EDGE_CURVE('E48',#1194,#1153,#1192,.T.);
#1196=ORIENTED_EDGE('',*,*,#1195,.F.);
#1197=DIRECTION('',(0.,-1.,0.));
#1198=VECTOR('',#1197,1.);
#1199=CARTESIAN_POINT('',(11.5588692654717,0.508,4.1928692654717));
#1200=LINE('',#1199,#1198);
#1201=EDGE_CURVE('E915',#1194,#280,#1200,.T.);
#1202=ORIENTED_EDGE('',*,*,#1201,.T.);
#1203=EDGE_LOOP('',(#1187,#1188,#1196,#1202));
#1204=FACE_BOUND('',#1203,.T.);
#1205=ADVANCED_FACE('F544',(#1204),#1186,.F.);
#1206=CARTESIAN_POINT('',(10.4812385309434,0.508,5.2705));
#1207=DIRECTION('',(0.,-1.,0.));
#1208=DIRECTION('',(0.,0.,-1.));
#1209=AXIS2_PLACEMENT_3D('',#1206,#1207,#1208);
#1210=CYLINDRICAL_SURFACE('',#1209,1.524);
#1211=ORIENTED_EDGE('',*,*,#290,.T.);
#1212=ORIENTED_EDGE('',*,*,#1201,.F.);
#1213=CARTESIAN_POINT('',(10.4812385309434,0.508,5.2705));
#1214=DIRECTION('',(0.,-1.,0.));
#1215=DIRECTION('',(0.,0.,1.));
#1216=AXIS2_PLACEMENT_3D('',#1213,#1214,#1215);
#1217=CIRCLE('',#1216,1.524);
#1218=CARTESIAN_POINT('',(10.4812385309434,0.508,3.7465));
#1219=VERTEX_POINT('',#1218);
#1220=EDGE_CURVE('E911',#1219,#1194,#1217,.T.);
#1221=ORIENTED_EDGE('',*,*,#1220,.F.);
#1222=DIRECTION('',(0.,-1.,0.));
#1223=VECTOR('',#1222,1.);
#1224=CARTESIAN_POINT('',(10.4812385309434,0.508,3.7465));
#1225=LINE('',#1224,#1223);
#1226=EDGE_CURVE('E917',#1219,#289,#1225,.T.);
#1227=ORIENTED_EDGE('',*,*,#1226,.T.);
#1228=EDGE_LOOP('',(#1211,#1212,#1221,#1227));
#1229=FACE_BOUND('',#1228,.T.);
#1230=ADVANCED_FACE('F555',(#1229),#1210,.F.);
#1231=CARTESIAN_POINT('',(10.4812385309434,0.508,3.7465));
#1232=DIRECTION('',(0.,0.,-1.));
#1233=DIRECTION('',(-1.,0.,0.));
#1234=AXIS2_PLACEMENT_3D('',#1231,#1232,#1233);
#1235=PLANE('',#1234);
#1236=ORIENTED_EDGE('',*,*,#298,.T.);
#1237=ORIENTED_EDGE('',*,*,#1226,.F.);
#1238=DIRECTION('',(1.,0.,0.));
#1239=VECTOR('',#1238,1.);
#1240=CARTESIAN_POINT('',(10.4812385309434,0.508,3.7465));
#1241=LINE('',#1240,#1239);
#1242=CARTESIAN_POINT('',(-10.4812385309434,0.508,3.7465));
#1243=VERTEX_POINT('',#1242);
#1244=EDGE_CURVE('E908',#1243,#1219,#1241,.T.);
#1245=ORIENTED_EDGE('',*,*,#1244,.F.);
#1246=DIRECTION('',(0.,-1.,0.));
#1247=VECTOR('',#1246,1.);
#1248=CARTESIAN_POINT('',(-10.4812385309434,0.508,3.7465));
#1249=LINE('',#1248,#1247);
#1250=EDGE_CURVE('E919',#1243,#297,#1249,.T.);
#1251=ORIENTED_EDGE('',*,*,#1250,.T.);
#1252=EDGE_LOOP('',(#1236,#1237,#1245,#1251));
#1253=FACE_BOUND('',#1252,.T.);
#1254=ADVANCED_FACE('F551',(#1253),#1235,.F.);
#1255=CARTESIAN_POINT('',(-10.4812385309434,0.508,5.2705));
#1256=DIRECTION('',(0.,-1.,0.));
#1257=DIRECTION('',(0.,0.,-1.));
#1258=AXIS2_PLACEMENT_3D('',#1255,#1256,#1257);
#1259=CYLINDRICAL_SURFACE('',#1258,1.524);
#1260=ORIENTED_EDGE('',*,*,#307,.T.);
#1261=ORIENTED_EDGE('',*,*,#1250,.F.);
#1262=CARTESIAN_POINT('',(-10.4812385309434,0.508,5.2705));
#1263=DIRECTION('',(0.,-1.,0.));
#1264=DIRECTION('',(0.,0.,1.));
#1265=AXIS2_PLACEMENT_3D('',#1262,#1263,#1264);
#1266=CIRCLE('',#1265,1.524);
#1267=CARTESIAN_POINT('',(-11.5588692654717,0.508,4.1928692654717));
#1268=VERTEX_POINT('',#1267);
#1269=EDGE_CURVE('E905',#1268,#1243,#1266,.T.);
#1270=ORIENTED_EDGE('',*,*,#1269,.F.);
#1271=DIRECTION('',(0.,-1.,0.));
#1272=VECTOR('',#1271,1.);
#1273=CARTESIAN_POINT('',(-11.5588692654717,0.508,4.1928692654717));
#1274=LINE('',#1273,#1272);
#1275=EDGE_CURVE('E255',#1268,#306,#1274,.T.);
#1276=ORIENTED_EDGE('',*,*,#1275,.T.);
#1277=EDGE_LOOP('',(#1260,#1261,#1270,#1276));
#1278=FACE_BOUND('',#1277,.T.);
#1279=ADVANCED_FACE('F548',(#1278),#1259,.F.);
#1280=CARTESIAN_POINT('',(-11.5588692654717,0.508,4.1928692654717));
#1281=DIRECTION('',(-0.707106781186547,0.,-0.707106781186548));
#1282=DIRECTION('',(-0.707106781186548,0.,0.707106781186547));
#1283=AXIS2_PLACEMENT_3D('',#1280,#1281,#1282);
#1284=PLANE('',#1283);
#1285=ORIENTED_EDGE('',*,*,#315,.T.);
#1286=ORIENTED_EDGE('',*,*,#1275,.F.);
#1287=DIRECTION('',(0.707106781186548,0.,-0.707106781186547));
#1288=VECTOR('',#1287,1.);
#1289=CARTESIAN_POINT('',(-11.5588692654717,0.508,4.1928692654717));
#1290=LINE('',#1289,#1288);
#1291=EDGE_CURVE('E251',#1155,#1268,#1290,.T.);
#1292=ORIENTED_EDGE('',*,*,#1291,.F.);
#1293=ORIENTED_EDGE('',*,*,#1177,.T.);
#1294=EDGE_LOOP('',(#1285,#1286,#1292,#1293));
#1295=FACE_BOUND('',#1294,.T.);
#1296=ADVANCED_FACE('F247',(#1295),#1284,.F.);
#1297=CARTESIAN_POINT('',(-10.4812385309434,0.508,5.2705));
#1298=DIRECTION('',(0.,1.,0.));
#1299=DIRECTION('',(0.,0.,1.));
#1300=AXIS2_PLACEMENT_3D('',#1297,#1298,#1299);
#1301=PLANE('',#1300);
#1302=ORIENTED_EDGE('',*,*,#1156,.T.);
#1303=ORIENTED_EDGE('',*,*,#1291,.T.);
#1304=ORIENTED_EDGE('',*,*,#1269,.T.);
#1305=ORIENTED_EDGE('',*,*,#1244,.T.);
#1306=ORIENTED_EDGE('',*,*,#1220,.T.);
#1307=ORIENTED_EDGE('',*,*,#1195,.T.);
#1308=EDGE_LOOP('',(#1302,#1303,#1304,#1305,#1306,#1307));
#1309=FACE_BOUND('',#1308,.T.);
#1310=ADVANCED_FACE('F547',(#1309),#1301,.F.);
#1311=CLOSED_SHELL('',(#59,#142,#183,#219,#259,#345,#376,#394,#470,#503,#529,#574,#592,#610,
#628,#662,#702,#762,#838,#862,#886,#924,#942,#960,#978,#1010,#1032,#1044,#1056,#1070,#1084,
#1104,#1113,#1133,#1142,#1181,#1205,#1230,#1254,#1279,#1296,#1310));
#1312=MANIFOLD_SOLID_BREP('B2',#1311);
#1313=ADVANCED_BREP_SHAPE_REPRESENTATION('',(#18,#1312),#14);
#1314=SHAPE_DEFINITION_REPRESENTATION(#9,#1313);
ENDSEC;
END-ISO-10303-21;
